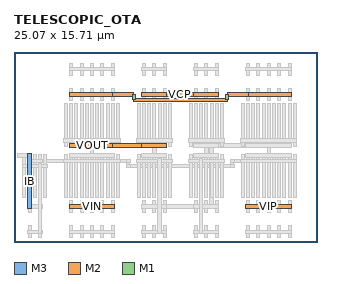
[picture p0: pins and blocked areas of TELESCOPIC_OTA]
MACRO TELESCOPIC_OTA
  ORIGIN 0 0 ;
  FOREIGN TELESCOPIC_OTA 0 0 ;
  SIZE 25.07 BY 15.71 ;
  PIN IB
    DIRECTION INOUT ;
    USE SIGNAL ;
    PORT 
      LAYER M3 ;
        RECT 1.15 2.78 1.43 7.3 ;
    END
  END IB
  PIN VCN
    DIRECTION INOUT ;
    USE SIGNAL ;
    PORT 
      LAYER M2 ;
        RECT 4.56 12.04 8.34 12.32 ;
      LAYER M2 ;
        RECT 19.18 12.04 22.96 12.32 ;
      LAYER M2 ;
        RECT 8.17 12.04 9.89 12.32 ;
      LAYER M1 ;
        RECT 9.765 11.76 10.015 12.18 ;
      LAYER M2 ;
        RECT 9.89 11.62 17.63 11.9 ;
      LAYER M1 ;
        RECT 17.505 11.76 17.755 12.18 ;
      LAYER M2 ;
        RECT 17.63 12.04 19.35 12.32 ;
    END
  END VCN
  PIN VOUT
    DIRECTION INOUT ;
    USE SIGNAL ;
    PORT 
      LAYER M2 ;
        RECT 4.56 7.84 8.34 8.12 ;
      LAYER M2 ;
        RECT 10.58 7.84 12.64 8.12 ;
      LAYER M2 ;
        RECT 8.17 7.84 10.75 8.12 ;
    END
  END VOUT
  PIN VIP
    DIRECTION INOUT ;
    USE SIGNAL ;
    PORT 
      LAYER M2 ;
        RECT 19.18 2.8 22.96 3.08 ;
    END
  END VIP
  PIN VIN
    DIRECTION INOUT ;
    USE SIGNAL ;
    PORT 
      LAYER M2 ;
        RECT 4.56 2.8 8.34 3.08 ;
    END
  END VIN
  PIN VCP
    DIRECTION INOUT ;
    USE SIGNAL ;
    PORT 
      LAYER M2 ;
        RECT 10.58 12.04 12.64 12.32 ;
      LAYER M2 ;
        RECT 14.88 12.04 16.94 12.32 ;
      LAYER M2 ;
        RECT 12.47 12.04 15.05 12.32 ;
    END
  END VCP
  OBS 
  LAYER M2 ;
        RECT 1.12 6.58 2.32 6.86 ;
  LAYER M2 ;
        RECT 4.13 6.58 8.77 6.86 ;
  LAYER M2 ;
        RECT 18.75 6.58 23.39 6.86 ;
  LAYER M2 ;
        RECT 2.15 6.58 4.3 6.86 ;
  LAYER M2 ;
        RECT 8.6 6.58 9.46 6.86 ;
  LAYER M1 ;
        RECT 9.335 6.3 9.585 6.72 ;
  LAYER M2 ;
        RECT 9.46 6.16 18.06 6.44 ;
  LAYER M1 ;
        RECT 17.935 6.3 18.185 6.72 ;
  LAYER M2 ;
        RECT 18.06 6.58 18.92 6.86 ;
  LAYER M1 ;
        RECT 9.335 6.215 9.585 6.385 ;
  LAYER M2 ;
        RECT 9.29 6.16 9.63 6.44 ;
  LAYER M1 ;
        RECT 9.335 6.635 9.585 6.805 ;
  LAYER M2 ;
        RECT 9.29 6.58 9.63 6.86 ;
  LAYER M1 ;
        RECT 17.935 6.215 18.185 6.385 ;
  LAYER M2 ;
        RECT 17.89 6.16 18.23 6.44 ;
  LAYER M1 ;
        RECT 17.935 6.635 18.185 6.805 ;
  LAYER M2 ;
        RECT 17.89 6.58 18.23 6.86 ;
  LAYER M1 ;
        RECT 9.335 6.215 9.585 6.385 ;
  LAYER M2 ;
        RECT 9.29 6.16 9.63 6.44 ;
  LAYER M1 ;
        RECT 9.335 6.635 9.585 6.805 ;
  LAYER M2 ;
        RECT 9.29 6.58 9.63 6.86 ;
  LAYER M1 ;
        RECT 17.935 6.215 18.185 6.385 ;
  LAYER M2 ;
        RECT 17.89 6.16 18.23 6.44 ;
  LAYER M1 ;
        RECT 17.935 6.635 18.185 6.805 ;
  LAYER M2 ;
        RECT 17.89 6.58 18.23 6.86 ;
  LAYER M2 ;
        RECT 14.88 7 16.94 7.28 ;
  LAYER M2 ;
        RECT 14.45 8.26 17.37 8.54 ;
  LAYER M2 ;
        RECT 15.75 7 16.07 7.28 ;
  LAYER M3 ;
        RECT 15.77 7.14 16.05 8.4 ;
  LAYER M2 ;
        RECT 15.75 8.26 16.07 8.54 ;
  LAYER M2 ;
        RECT 15.75 7 16.07 7.28 ;
  LAYER M3 ;
        RECT 15.77 6.98 16.05 7.3 ;
  LAYER M2 ;
        RECT 15.75 8.26 16.07 8.54 ;
  LAYER M3 ;
        RECT 15.77 8.24 16.05 8.56 ;
  LAYER M2 ;
        RECT 15.75 7 16.07 7.28 ;
  LAYER M3 ;
        RECT 15.77 6.98 16.05 7.3 ;
  LAYER M2 ;
        RECT 15.75 8.26 16.07 8.54 ;
  LAYER M3 ;
        RECT 15.77 8.24 16.05 8.56 ;
  LAYER M2 ;
        RECT 10.58 2.8 12.64 3.08 ;
  LAYER M2 ;
        RECT 14.88 2.8 16.94 3.08 ;
  LAYER M2 ;
        RECT 14.88 7.84 16.94 8.12 ;
  LAYER M2 ;
        RECT 19.18 7.84 22.96 8.12 ;
  LAYER M2 ;
        RECT 12.47 2.8 15.05 3.08 ;
  LAYER M2 ;
        RECT 16.18 2.8 16.5 3.08 ;
  LAYER M3 ;
        RECT 16.2 2.94 16.48 7.98 ;
  LAYER M2 ;
        RECT 16.18 7.84 16.5 8.12 ;
  LAYER M2 ;
        RECT 16.77 7.84 19.35 8.12 ;
  LAYER M2 ;
        RECT 16.18 2.8 16.5 3.08 ;
  LAYER M3 ;
        RECT 16.2 2.78 16.48 3.1 ;
  LAYER M2 ;
        RECT 16.18 7.84 16.5 8.12 ;
  LAYER M3 ;
        RECT 16.2 7.82 16.48 8.14 ;
  LAYER M2 ;
        RECT 16.18 2.8 16.5 3.08 ;
  LAYER M3 ;
        RECT 16.2 2.78 16.48 3.1 ;
  LAYER M2 ;
        RECT 16.18 7.84 16.5 8.12 ;
  LAYER M3 ;
        RECT 16.2 7.82 16.48 8.14 ;
  LAYER M2 ;
        RECT 16.18 2.8 16.5 3.08 ;
  LAYER M3 ;
        RECT 16.2 2.78 16.48 3.1 ;
  LAYER M2 ;
        RECT 16.18 7.84 16.5 8.12 ;
  LAYER M3 ;
        RECT 16.2 7.82 16.48 8.14 ;
  LAYER M2 ;
        RECT 16.18 2.8 16.5 3.08 ;
  LAYER M3 ;
        RECT 16.2 2.78 16.48 3.1 ;
  LAYER M2 ;
        RECT 16.18 7.84 16.5 8.12 ;
  LAYER M3 ;
        RECT 16.2 7.82 16.48 8.14 ;
  LAYER M2 ;
        RECT 10.58 7 12.64 7.28 ;
  LAYER M2 ;
        RECT 10.15 8.26 13.07 8.54 ;
  LAYER M2 ;
        RECT 11.45 7 11.77 7.28 ;
  LAYER M3 ;
        RECT 11.47 7.14 11.75 8.4 ;
  LAYER M2 ;
        RECT 11.45 8.26 11.77 8.54 ;
  LAYER M2 ;
        RECT 11.45 7 11.77 7.28 ;
  LAYER M3 ;
        RECT 11.47 6.98 11.75 7.3 ;
  LAYER M2 ;
        RECT 11.45 8.26 11.77 8.54 ;
  LAYER M3 ;
        RECT 11.47 8.24 11.75 8.56 ;
  LAYER M2 ;
        RECT 11.45 7 11.77 7.28 ;
  LAYER M3 ;
        RECT 11.47 6.98 11.75 7.3 ;
  LAYER M2 ;
        RECT 11.45 8.26 11.77 8.54 ;
  LAYER M3 ;
        RECT 11.47 8.24 11.75 8.56 ;
  LAYER M2 ;
        RECT 19.18 7 22.96 7.28 ;
  LAYER M2 ;
        RECT 18.75 8.26 23.39 8.54 ;
  LAYER M2 ;
        RECT 20.91 7 21.23 7.28 ;
  LAYER M3 ;
        RECT 20.93 7.14 21.21 8.4 ;
  LAYER M2 ;
        RECT 20.91 8.26 21.23 8.54 ;
  LAYER M2 ;
        RECT 20.91 7 21.23 7.28 ;
  LAYER M3 ;
        RECT 20.93 6.98 21.21 7.3 ;
  LAYER M2 ;
        RECT 20.91 8.26 21.23 8.54 ;
  LAYER M3 ;
        RECT 20.93 8.24 21.21 8.56 ;
  LAYER M2 ;
        RECT 20.91 7 21.23 7.28 ;
  LAYER M3 ;
        RECT 20.93 6.98 21.21 7.3 ;
  LAYER M2 ;
        RECT 20.91 8.26 21.23 8.54 ;
  LAYER M3 ;
        RECT 20.93 8.24 21.21 8.56 ;
  LAYER M2 ;
        RECT 4.56 7 8.34 7.28 ;
  LAYER M2 ;
        RECT 4.13 8.26 8.77 8.54 ;
  LAYER M2 ;
        RECT 6.29 7 6.61 7.28 ;
  LAYER M3 ;
        RECT 6.31 7.14 6.59 8.4 ;
  LAYER M2 ;
        RECT 6.29 8.26 6.61 8.54 ;
  LAYER M2 ;
        RECT 6.29 7 6.61 7.28 ;
  LAYER M3 ;
        RECT 6.31 6.98 6.59 7.3 ;
  LAYER M2 ;
        RECT 6.29 8.26 6.61 8.54 ;
  LAYER M3 ;
        RECT 6.31 8.24 6.59 8.56 ;
  LAYER M2 ;
        RECT 6.29 7 6.61 7.28 ;
  LAYER M3 ;
        RECT 6.31 6.98 6.59 7.3 ;
  LAYER M2 ;
        RECT 6.29 8.26 6.61 8.54 ;
  LAYER M3 ;
        RECT 6.31 8.24 6.59 8.56 ;
  LAYER M1 ;
        RECT 1.165 3.695 1.415 7.225 ;
  LAYER M1 ;
        RECT 1.165 2.435 1.415 3.445 ;
  LAYER M1 ;
        RECT 1.165 0.335 1.415 1.345 ;
  LAYER M1 ;
        RECT 0.735 3.695 0.985 7.225 ;
  LAYER M1 ;
        RECT 1.595 3.695 1.845 7.225 ;
  LAYER M1 ;
        RECT 2.025 3.695 2.275 7.225 ;
  LAYER M1 ;
        RECT 2.025 2.435 2.275 3.445 ;
  LAYER M1 ;
        RECT 2.025 0.335 2.275 1.345 ;
  LAYER M1 ;
        RECT 2.455 3.695 2.705 7.225 ;
  LAYER M2 ;
        RECT 0.26 7 1.46 7.28 ;
  LAYER M2 ;
        RECT 1.12 2.8 2.32 3.08 ;
  LAYER M2 ;
        RECT 1.12 0.7 2.32 0.98 ;
  LAYER M2 ;
        RECT 0.69 6.16 2.75 6.44 ;
  LAYER M3 ;
        RECT 1.15 2.78 1.43 7.3 ;
  LAYER M2 ;
        RECT 1.12 6.58 2.32 6.86 ;
  LAYER M3 ;
        RECT 2.01 0.68 2.29 6.46 ;
  LAYER M1 ;
        RECT 16.645 3.695 16.895 7.225 ;
  LAYER M1 ;
        RECT 16.645 2.435 16.895 3.445 ;
  LAYER M1 ;
        RECT 16.645 0.335 16.895 1.345 ;
  LAYER M1 ;
        RECT 17.075 3.695 17.325 7.225 ;
  LAYER M1 ;
        RECT 16.215 3.695 16.465 7.225 ;
  LAYER M1 ;
        RECT 15.785 3.695 16.035 7.225 ;
  LAYER M1 ;
        RECT 15.785 2.435 16.035 3.445 ;
  LAYER M1 ;
        RECT 15.785 0.335 16.035 1.345 ;
  LAYER M1 ;
        RECT 15.355 3.695 15.605 7.225 ;
  LAYER M1 ;
        RECT 14.925 3.695 15.175 7.225 ;
  LAYER M1 ;
        RECT 14.925 2.435 15.175 3.445 ;
  LAYER M1 ;
        RECT 14.925 0.335 15.175 1.345 ;
  LAYER M1 ;
        RECT 14.495 3.695 14.745 7.225 ;
  LAYER M2 ;
        RECT 14.88 0.7 16.94 0.98 ;
  LAYER M2 ;
        RECT 14.45 6.58 17.37 6.86 ;
  LAYER M2 ;
        RECT 14.88 7 16.94 7.28 ;
  LAYER M2 ;
        RECT 14.88 2.8 16.94 3.08 ;
  LAYER M3 ;
        RECT 15.34 0.68 15.62 6.88 ;
  LAYER M1 ;
        RECT 10.625 3.695 10.875 7.225 ;
  LAYER M1 ;
        RECT 10.625 2.435 10.875 3.445 ;
  LAYER M1 ;
        RECT 10.625 0.335 10.875 1.345 ;
  LAYER M1 ;
        RECT 10.195 3.695 10.445 7.225 ;
  LAYER M1 ;
        RECT 11.055 3.695 11.305 7.225 ;
  LAYER M1 ;
        RECT 11.485 3.695 11.735 7.225 ;
  LAYER M1 ;
        RECT 11.485 2.435 11.735 3.445 ;
  LAYER M1 ;
        RECT 11.485 0.335 11.735 1.345 ;
  LAYER M1 ;
        RECT 11.915 3.695 12.165 7.225 ;
  LAYER M1 ;
        RECT 12.345 3.695 12.595 7.225 ;
  LAYER M1 ;
        RECT 12.345 2.435 12.595 3.445 ;
  LAYER M1 ;
        RECT 12.345 0.335 12.595 1.345 ;
  LAYER M1 ;
        RECT 12.775 3.695 13.025 7.225 ;
  LAYER M2 ;
        RECT 10.58 0.7 12.64 0.98 ;
  LAYER M2 ;
        RECT 10.15 6.58 13.07 6.86 ;
  LAYER M2 ;
        RECT 10.58 7 12.64 7.28 ;
  LAYER M2 ;
        RECT 10.58 2.8 12.64 3.08 ;
  LAYER M3 ;
        RECT 11.9 0.68 12.18 6.88 ;
  LAYER M1 ;
        RECT 22.665 7.895 22.915 11.425 ;
  LAYER M1 ;
        RECT 22.665 11.675 22.915 12.685 ;
  LAYER M1 ;
        RECT 22.665 13.775 22.915 14.785 ;
  LAYER M1 ;
        RECT 23.095 7.895 23.345 11.425 ;
  LAYER M1 ;
        RECT 22.235 7.895 22.485 11.425 ;
  LAYER M1 ;
        RECT 21.805 7.895 22.055 11.425 ;
  LAYER M1 ;
        RECT 21.805 11.675 22.055 12.685 ;
  LAYER M1 ;
        RECT 21.805 13.775 22.055 14.785 ;
  LAYER M1 ;
        RECT 21.375 7.895 21.625 11.425 ;
  LAYER M1 ;
        RECT 20.945 7.895 21.195 11.425 ;
  LAYER M1 ;
        RECT 20.945 11.675 21.195 12.685 ;
  LAYER M1 ;
        RECT 20.945 13.775 21.195 14.785 ;
  LAYER M1 ;
        RECT 20.515 7.895 20.765 11.425 ;
  LAYER M1 ;
        RECT 20.085 7.895 20.335 11.425 ;
  LAYER M1 ;
        RECT 20.085 11.675 20.335 12.685 ;
  LAYER M1 ;
        RECT 20.085 13.775 20.335 14.785 ;
  LAYER M1 ;
        RECT 19.655 7.895 19.905 11.425 ;
  LAYER M1 ;
        RECT 19.225 7.895 19.475 11.425 ;
  LAYER M1 ;
        RECT 19.225 11.675 19.475 12.685 ;
  LAYER M1 ;
        RECT 19.225 13.775 19.475 14.785 ;
  LAYER M1 ;
        RECT 18.795 7.895 19.045 11.425 ;
  LAYER M2 ;
        RECT 19.18 14.14 22.96 14.42 ;
  LAYER M2 ;
        RECT 19.18 7.84 22.96 8.12 ;
  LAYER M2 ;
        RECT 19.18 12.04 22.96 12.32 ;
  LAYER M2 ;
        RECT 18.75 8.26 23.39 8.54 ;
  LAYER M1 ;
        RECT 4.605 7.895 4.855 11.425 ;
  LAYER M1 ;
        RECT 4.605 11.675 4.855 12.685 ;
  LAYER M1 ;
        RECT 4.605 13.775 4.855 14.785 ;
  LAYER M1 ;
        RECT 4.175 7.895 4.425 11.425 ;
  LAYER M1 ;
        RECT 5.035 7.895 5.285 11.425 ;
  LAYER M1 ;
        RECT 5.465 7.895 5.715 11.425 ;
  LAYER M1 ;
        RECT 5.465 11.675 5.715 12.685 ;
  LAYER M1 ;
        RECT 5.465 13.775 5.715 14.785 ;
  LAYER M1 ;
        RECT 5.895 7.895 6.145 11.425 ;
  LAYER M1 ;
        RECT 6.325 7.895 6.575 11.425 ;
  LAYER M1 ;
        RECT 6.325 11.675 6.575 12.685 ;
  LAYER M1 ;
        RECT 6.325 13.775 6.575 14.785 ;
  LAYER M1 ;
        RECT 6.755 7.895 7.005 11.425 ;
  LAYER M1 ;
        RECT 7.185 7.895 7.435 11.425 ;
  LAYER M1 ;
        RECT 7.185 11.675 7.435 12.685 ;
  LAYER M1 ;
        RECT 7.185 13.775 7.435 14.785 ;
  LAYER M1 ;
        RECT 7.615 7.895 7.865 11.425 ;
  LAYER M1 ;
        RECT 8.045 7.895 8.295 11.425 ;
  LAYER M1 ;
        RECT 8.045 11.675 8.295 12.685 ;
  LAYER M1 ;
        RECT 8.045 13.775 8.295 14.785 ;
  LAYER M1 ;
        RECT 8.475 7.895 8.725 11.425 ;
  LAYER M2 ;
        RECT 4.56 14.14 8.34 14.42 ;
  LAYER M2 ;
        RECT 4.56 7.84 8.34 8.12 ;
  LAYER M2 ;
        RECT 4.56 12.04 8.34 12.32 ;
  LAYER M2 ;
        RECT 4.13 8.26 8.77 8.54 ;
  LAYER M1 ;
        RECT 19.225 3.695 19.475 7.225 ;
  LAYER M1 ;
        RECT 19.225 2.435 19.475 3.445 ;
  LAYER M1 ;
        RECT 19.225 0.335 19.475 1.345 ;
  LAYER M1 ;
        RECT 18.795 3.695 19.045 7.225 ;
  LAYER M1 ;
        RECT 19.655 3.695 19.905 7.225 ;
  LAYER M1 ;
        RECT 20.085 3.695 20.335 7.225 ;
  LAYER M1 ;
        RECT 20.085 2.435 20.335 3.445 ;
  LAYER M1 ;
        RECT 20.085 0.335 20.335 1.345 ;
  LAYER M1 ;
        RECT 20.515 3.695 20.765 7.225 ;
  LAYER M1 ;
        RECT 20.945 3.695 21.195 7.225 ;
  LAYER M1 ;
        RECT 20.945 2.435 21.195 3.445 ;
  LAYER M1 ;
        RECT 20.945 0.335 21.195 1.345 ;
  LAYER M1 ;
        RECT 21.375 3.695 21.625 7.225 ;
  LAYER M1 ;
        RECT 21.805 3.695 22.055 7.225 ;
  LAYER M1 ;
        RECT 21.805 2.435 22.055 3.445 ;
  LAYER M1 ;
        RECT 21.805 0.335 22.055 1.345 ;
  LAYER M1 ;
        RECT 22.235 3.695 22.485 7.225 ;
  LAYER M1 ;
        RECT 22.665 3.695 22.915 7.225 ;
  LAYER M1 ;
        RECT 22.665 2.435 22.915 3.445 ;
  LAYER M1 ;
        RECT 22.665 0.335 22.915 1.345 ;
  LAYER M1 ;
        RECT 23.095 3.695 23.345 7.225 ;
  LAYER M2 ;
        RECT 19.18 0.7 22.96 0.98 ;
  LAYER M2 ;
        RECT 19.18 7 22.96 7.28 ;
  LAYER M2 ;
        RECT 19.18 2.8 22.96 3.08 ;
  LAYER M2 ;
        RECT 18.75 6.58 23.39 6.86 ;
  LAYER M1 ;
        RECT 8.045 3.695 8.295 7.225 ;
  LAYER M1 ;
        RECT 8.045 2.435 8.295 3.445 ;
  LAYER M1 ;
        RECT 8.045 0.335 8.295 1.345 ;
  LAYER M1 ;
        RECT 8.475 3.695 8.725 7.225 ;
  LAYER M1 ;
        RECT 7.615 3.695 7.865 7.225 ;
  LAYER M1 ;
        RECT 7.185 3.695 7.435 7.225 ;
  LAYER M1 ;
        RECT 7.185 2.435 7.435 3.445 ;
  LAYER M1 ;
        RECT 7.185 0.335 7.435 1.345 ;
  LAYER M1 ;
        RECT 6.755 3.695 7.005 7.225 ;
  LAYER M1 ;
        RECT 6.325 3.695 6.575 7.225 ;
  LAYER M1 ;
        RECT 6.325 2.435 6.575 3.445 ;
  LAYER M1 ;
        RECT 6.325 0.335 6.575 1.345 ;
  LAYER M1 ;
        RECT 5.895 3.695 6.145 7.225 ;
  LAYER M1 ;
        RECT 5.465 3.695 5.715 7.225 ;
  LAYER M1 ;
        RECT 5.465 2.435 5.715 3.445 ;
  LAYER M1 ;
        RECT 5.465 0.335 5.715 1.345 ;
  LAYER M1 ;
        RECT 5.035 3.695 5.285 7.225 ;
  LAYER M1 ;
        RECT 4.605 3.695 4.855 7.225 ;
  LAYER M1 ;
        RECT 4.605 2.435 4.855 3.445 ;
  LAYER M1 ;
        RECT 4.605 0.335 4.855 1.345 ;
  LAYER M1 ;
        RECT 4.175 3.695 4.425 7.225 ;
  LAYER M2 ;
        RECT 4.56 0.7 8.34 0.98 ;
  LAYER M2 ;
        RECT 4.56 7 8.34 7.28 ;
  LAYER M2 ;
        RECT 4.56 2.8 8.34 3.08 ;
  LAYER M2 ;
        RECT 4.13 6.58 8.77 6.86 ;
  LAYER M1 ;
        RECT 14.925 7.895 15.175 11.425 ;
  LAYER M1 ;
        RECT 14.925 11.675 15.175 12.685 ;
  LAYER M1 ;
        RECT 14.925 13.775 15.175 14.785 ;
  LAYER M1 ;
        RECT 14.495 7.895 14.745 11.425 ;
  LAYER M1 ;
        RECT 15.355 7.895 15.605 11.425 ;
  LAYER M1 ;
        RECT 15.785 7.895 16.035 11.425 ;
  LAYER M1 ;
        RECT 15.785 11.675 16.035 12.685 ;
  LAYER M1 ;
        RECT 15.785 13.775 16.035 14.785 ;
  LAYER M1 ;
        RECT 16.215 7.895 16.465 11.425 ;
  LAYER M1 ;
        RECT 16.645 7.895 16.895 11.425 ;
  LAYER M1 ;
        RECT 16.645 11.675 16.895 12.685 ;
  LAYER M1 ;
        RECT 16.645 13.775 16.895 14.785 ;
  LAYER M1 ;
        RECT 17.075 7.895 17.325 11.425 ;
  LAYER M2 ;
        RECT 14.88 14.14 16.94 14.42 ;
  LAYER M2 ;
        RECT 14.88 7.84 16.94 8.12 ;
  LAYER M2 ;
        RECT 14.88 12.04 16.94 12.32 ;
  LAYER M2 ;
        RECT 14.45 8.26 17.37 8.54 ;
  LAYER M1 ;
        RECT 12.345 7.895 12.595 11.425 ;
  LAYER M1 ;
        RECT 12.345 11.675 12.595 12.685 ;
  LAYER M1 ;
        RECT 12.345 13.775 12.595 14.785 ;
  LAYER M1 ;
        RECT 12.775 7.895 13.025 11.425 ;
  LAYER M1 ;
        RECT 11.915 7.895 12.165 11.425 ;
  LAYER M1 ;
        RECT 11.485 7.895 11.735 11.425 ;
  LAYER M1 ;
        RECT 11.485 11.675 11.735 12.685 ;
  LAYER M1 ;
        RECT 11.485 13.775 11.735 14.785 ;
  LAYER M1 ;
        RECT 11.055 7.895 11.305 11.425 ;
  LAYER M1 ;
        RECT 10.625 7.895 10.875 11.425 ;
  LAYER M1 ;
        RECT 10.625 11.675 10.875 12.685 ;
  LAYER M1 ;
        RECT 10.625 13.775 10.875 14.785 ;
  LAYER M1 ;
        RECT 10.195 7.895 10.445 11.425 ;
  LAYER M2 ;
        RECT 10.58 14.14 12.64 14.42 ;
  LAYER M2 ;
        RECT 10.58 7.84 12.64 8.12 ;
  LAYER M2 ;
        RECT 10.58 12.04 12.64 12.32 ;
  LAYER M2 ;
        RECT 10.15 8.26 13.07 8.54 ;
  END 
END TELESCOPIC_OTA
